VERSION 5.7 ;
  NOWIREEXTENSIONATPIN ON ;
  DIVIDERCHAR "/" ;
  BUSBITCHARS "[]" ;
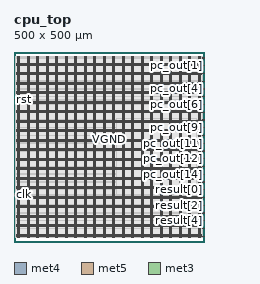
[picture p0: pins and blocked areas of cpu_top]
MACRO cpu_top
  CLASS BLOCK ;
  FOREIGN cpu_top ;
  ORIGIN 0.000 0.000 ;
  SIZE 500.000 BY 500.000 ;
  PIN VGND
    DIRECTION INOUT ;
    USE GROUND ;
    PORT
      LAYER met4 ;
        RECT 13.020 10.640 14.620 487.120 ;
    END
    PORT
      LAYER met4 ;
        RECT 38.020 10.640 39.620 487.120 ;
    END
    PORT
      LAYER met4 ;
        RECT 63.020 10.640 64.620 487.120 ;
    END
    PORT
      LAYER met4 ;
        RECT 88.020 10.640 89.620 487.120 ;
    END
    PORT
      LAYER met4 ;
        RECT 113.020 10.640 114.620 487.120 ;
    END
    PORT
      LAYER met4 ;
        RECT 138.020 10.640 139.620 487.120 ;
    END
    PORT
      LAYER met4 ;
        RECT 163.020 10.640 164.620 487.120 ;
    END
    PORT
      LAYER met4 ;
        RECT 188.020 10.640 189.620 487.120 ;
    END
    PORT
      LAYER met4 ;
        RECT 213.020 10.640 214.620 487.120 ;
    END
    PORT
      LAYER met4 ;
        RECT 238.020 10.640 239.620 487.120 ;
    END
    PORT
      LAYER met4 ;
        RECT 263.020 10.640 264.620 487.120 ;
    END
    PORT
      LAYER met4 ;
        RECT 288.020 10.640 289.620 487.120 ;
    END
    PORT
      LAYER met4 ;
        RECT 313.020 10.640 314.620 487.120 ;
    END
    PORT
      LAYER met4 ;
        RECT 338.020 10.640 339.620 487.120 ;
    END
    PORT
      LAYER met4 ;
        RECT 363.020 10.640 364.620 487.120 ;
    END
    PORT
      LAYER met4 ;
        RECT 388.020 10.640 389.620 487.120 ;
    END
    PORT
      LAYER met4 ;
        RECT 413.020 10.640 414.620 487.120 ;
    END
    PORT
      LAYER met4 ;
        RECT 438.020 10.640 439.620 487.120 ;
    END
    PORT
      LAYER met4 ;
        RECT 463.020 10.640 464.620 487.120 ;
    END
    PORT
      LAYER met4 ;
        RECT 488.020 10.640 489.620 487.120 ;
    END
    PORT
      LAYER met5 ;
        RECT 5.280 18.380 494.280 19.980 ;
    END
    PORT
      LAYER met5 ;
        RECT 5.280 43.380 494.280 44.980 ;
    END
    PORT
      LAYER met5 ;
        RECT 5.280 68.380 494.280 69.980 ;
    END
    PORT
      LAYER met5 ;
        RECT 5.280 93.380 494.280 94.980 ;
    END
    PORT
      LAYER met5 ;
        RECT 5.280 118.380 494.280 119.980 ;
    END
    PORT
      LAYER met5 ;
        RECT 5.280 143.380 494.280 144.980 ;
    END
    PORT
      LAYER met5 ;
        RECT 5.280 168.380 494.280 169.980 ;
    END
    PORT
      LAYER met5 ;
        RECT 5.280 193.380 494.280 194.980 ;
    END
    PORT
      LAYER met5 ;
        RECT 5.280 218.380 494.280 219.980 ;
    END
    PORT
      LAYER met5 ;
        RECT 5.280 243.380 494.280 244.980 ;
    END
    PORT
      LAYER met5 ;
        RECT 5.280 268.380 494.280 269.980 ;
    END
    PORT
      LAYER met5 ;
        RECT 5.280 293.380 494.280 294.980 ;
    END
    PORT
      LAYER met5 ;
        RECT 5.280 318.380 494.280 319.980 ;
    END
    PORT
      LAYER met5 ;
        RECT 5.280 343.380 494.280 344.980 ;
    END
    PORT
      LAYER met5 ;
        RECT 5.280 368.380 494.280 369.980 ;
    END
    PORT
      LAYER met5 ;
        RECT 5.280 393.380 494.280 394.980 ;
    END
    PORT
      LAYER met5 ;
        RECT 5.280 418.380 494.280 419.980 ;
    END
    PORT
      LAYER met5 ;
        RECT 5.280 443.380 494.280 444.980 ;
    END
    PORT
      LAYER met5 ;
        RECT 5.280 468.380 494.280 469.980 ;
    END
  END VGND
  PIN VPWR
    DIRECTION INOUT ;
    USE POWER ;
    PORT
      LAYER met4 ;
        RECT 9.720 10.640 11.320 487.120 ;
    END
    PORT
      LAYER met4 ;
        RECT 34.720 10.640 36.320 487.120 ;
    END
    PORT
      LAYER met4 ;
        RECT 59.720 10.640 61.320 487.120 ;
    END
    PORT
      LAYER met4 ;
        RECT 84.720 10.640 86.320 487.120 ;
    END
    PORT
      LAYER met4 ;
        RECT 109.720 10.640 111.320 487.120 ;
    END
    PORT
      LAYER met4 ;
        RECT 134.720 10.640 136.320 487.120 ;
    END
    PORT
      LAYER met4 ;
        RECT 159.720 10.640 161.320 487.120 ;
    END
    PORT
      LAYER met4 ;
        RECT 184.720 10.640 186.320 487.120 ;
    END
    PORT
      LAYER met4 ;
        RECT 209.720 10.640 211.320 487.120 ;
    END
    PORT
      LAYER met4 ;
        RECT 234.720 10.640 236.320 487.120 ;
    END
    PORT
      LAYER met4 ;
        RECT 259.720 10.640 261.320 487.120 ;
    END
    PORT
      LAYER met4 ;
        RECT 284.720 10.640 286.320 487.120 ;
    END
    PORT
      LAYER met4 ;
        RECT 309.720 10.640 311.320 487.120 ;
    END
    PORT
      LAYER met4 ;
        RECT 334.720 10.640 336.320 487.120 ;
    END
    PORT
      LAYER met4 ;
        RECT 359.720 10.640 361.320 487.120 ;
    END
    PORT
      LAYER met4 ;
        RECT 384.720 10.640 386.320 487.120 ;
    END
    PORT
      LAYER met4 ;
        RECT 409.720 10.640 411.320 487.120 ;
    END
    PORT
      LAYER met4 ;
        RECT 434.720 10.640 436.320 487.120 ;
    END
    PORT
      LAYER met4 ;
        RECT 459.720 10.640 461.320 487.120 ;
    END
    PORT
      LAYER met4 ;
        RECT 484.720 10.640 486.320 487.120 ;
    END
    PORT
      LAYER met5 ;
        RECT 5.280 15.080 494.280 16.680 ;
    END
    PORT
      LAYER met5 ;
        RECT 5.280 40.080 494.280 41.680 ;
    END
    PORT
      LAYER met5 ;
        RECT 5.280 65.080 494.280 66.680 ;
    END
    PORT
      LAYER met5 ;
        RECT 5.280 90.080 494.280 91.680 ;
    END
    PORT
      LAYER met5 ;
        RECT 5.280 115.080 494.280 116.680 ;
    END
    PORT
      LAYER met5 ;
        RECT 5.280 140.080 494.280 141.680 ;
    END
    PORT
      LAYER met5 ;
        RECT 5.280 165.080 494.280 166.680 ;
    END
    PORT
      LAYER met5 ;
        RECT 5.280 190.080 494.280 191.680 ;
    END
    PORT
      LAYER met5 ;
        RECT 5.280 215.080 494.280 216.680 ;
    END
    PORT
      LAYER met5 ;
        RECT 5.280 240.080 494.280 241.680 ;
    END
    PORT
      LAYER met5 ;
        RECT 5.280 265.080 494.280 266.680 ;
    END
    PORT
      LAYER met5 ;
        RECT 5.280 290.080 494.280 291.680 ;
    END
    PORT
      LAYER met5 ;
        RECT 5.280 315.080 494.280 316.680 ;
    END
    PORT
      LAYER met5 ;
        RECT 5.280 340.080 494.280 341.680 ;
    END
    PORT
      LAYER met5 ;
        RECT 5.280 365.080 494.280 366.680 ;
    END
    PORT
      LAYER met5 ;
        RECT 5.280 390.080 494.280 391.680 ;
    END
    PORT
      LAYER met5 ;
        RECT 5.280 415.080 494.280 416.680 ;
    END
    PORT
      LAYER met5 ;
        RECT 5.280 440.080 494.280 441.680 ;
    END
    PORT
      LAYER met5 ;
        RECT 5.280 465.080 494.280 466.680 ;
    END
  END VPWR
  PIN clk
    DIRECTION INPUT ;
    USE SIGNAL ;
    ANTENNAGATEAREA 0.852000 ;
    PORT
      LAYER met3 ;
        RECT 0.000 123.800 4.000 124.400 ;
    END
  END clk
  PIN pc_out[0]
    DIRECTION OUTPUT TRISTATE ;
    USE SIGNAL ;
    ANTENNAGATEAREA 1.984500 ;
    ANTENNADIFFAREA 0.445500 ;
    PORT
      LAYER met3 ;
        RECT 496.000 484.200 500.000 484.800 ;
    END
  END pc_out[0]
  PIN pc_out[10]
    DIRECTION OUTPUT TRISTATE ;
    USE SIGNAL ;
    ANTENNAGATEAREA 1.363500 ;
    ANTENNADIFFAREA 0.445500 ;
    PORT
      LAYER met3 ;
        RECT 496.000 280.200 500.000 280.800 ;
    END
  END pc_out[10]
  PIN pc_out[11]
    DIRECTION OUTPUT TRISTATE ;
    USE SIGNAL ;
    ANTENNAGATEAREA 0.621000 ;
    ANTENNADIFFAREA 0.445500 ;
    PORT
      LAYER met3 ;
        RECT 496.000 259.800 500.000 260.400 ;
    END
  END pc_out[11]
  PIN pc_out[12]
    DIRECTION OUTPUT TRISTATE ;
    USE SIGNAL ;
    ANTENNAGATEAREA 1.363500 ;
    ANTENNADIFFAREA 0.445500 ;
    PORT
      LAYER met3 ;
        RECT 496.000 239.400 500.000 240.000 ;
    END
  END pc_out[12]
  PIN pc_out[13]
    DIRECTION OUTPUT TRISTATE ;
    USE SIGNAL ;
    ANTENNAGATEAREA 0.621000 ;
    ANTENNADIFFAREA 0.445500 ;
    PORT
      LAYER met3 ;
        RECT 496.000 219.000 500.000 219.600 ;
    END
  END pc_out[13]
  PIN pc_out[14]
    DIRECTION OUTPUT TRISTATE ;
    USE SIGNAL ;
    ANTENNAGATEAREA 1.237500 ;
    ANTENNADIFFAREA 0.445500 ;
    PORT
      LAYER met3 ;
        RECT 496.000 198.600 500.000 199.200 ;
    END
  END pc_out[14]
  PIN pc_out[15]
    DIRECTION OUTPUT TRISTATE ;
    USE SIGNAL ;
    ANTENNAGATEAREA 0.742500 ;
    ANTENNADIFFAREA 0.445500 ;
    PORT
      LAYER met3 ;
        RECT 496.000 178.200 500.000 178.800 ;
    END
  END pc_out[15]
  PIN pc_out[1]
    DIRECTION OUTPUT TRISTATE ;
    USE SIGNAL ;
    ANTENNAGATEAREA 1.489500 ;
    ANTENNADIFFAREA 0.445500 ;
    PORT
      LAYER met3 ;
        RECT 496.000 463.800 500.000 464.400 ;
    END
  END pc_out[1]
  PIN pc_out[2]
    DIRECTION OUTPUT TRISTATE ;
    USE SIGNAL ;
    ANTENNAGATEAREA 0.747000 ;
    ANTENNADIFFAREA 0.445500 ;
    PORT
      LAYER met3 ;
        RECT 496.000 443.400 500.000 444.000 ;
    END
  END pc_out[2]
  PIN pc_out[3]
    DIRECTION OUTPUT TRISTATE ;
    USE SIGNAL ;
    ANTENNAGATEAREA 0.373500 ;
    ANTENNADIFFAREA 0.445500 ;
    PORT
      LAYER met3 ;
        RECT 496.000 423.000 500.000 423.600 ;
    END
  END pc_out[3]
  PIN pc_out[4]
    DIRECTION OUTPUT TRISTATE ;
    USE SIGNAL ;
    ANTENNAGATEAREA 2.106000 ;
    ANTENNADIFFAREA 0.445500 ;
    PORT
      LAYER met3 ;
        RECT 496.000 402.600 500.000 403.200 ;
    END
  END pc_out[4]
  PIN pc_out[5]
    DIRECTION OUTPUT TRISTATE ;
    USE SIGNAL ;
    ANTENNAGATEAREA 1.363500 ;
    ANTENNADIFFAREA 0.445500 ;
    PORT
      LAYER met3 ;
        RECT 496.000 382.200 500.000 382.800 ;
    END
  END pc_out[5]
  PIN pc_out[6]
    DIRECTION OUTPUT TRISTATE ;
    USE SIGNAL ;
    ANTENNAGATEAREA 0.621000 ;
    ANTENNADIFFAREA 0.445500 ;
    PORT
      LAYER met3 ;
        RECT 496.000 361.800 500.000 362.400 ;
    END
  END pc_out[6]
  PIN pc_out[7]
    DIRECTION OUTPUT TRISTATE ;
    USE SIGNAL ;
    ANTENNAGATEAREA 1.489500 ;
    ANTENNADIFFAREA 0.445500 ;
    PORT
      LAYER met3 ;
        RECT 496.000 341.400 500.000 342.000 ;
    END
  END pc_out[7]
  PIN pc_out[8]
    DIRECTION OUTPUT TRISTATE ;
    USE SIGNAL ;
    ANTENNAGATEAREA 0.747000 ;
    ANTENNADIFFAREA 0.445500 ;
    PORT
      LAYER met3 ;
        RECT 496.000 321.000 500.000 321.600 ;
    END
  END pc_out[8]
  PIN pc_out[9]
    DIRECTION OUTPUT TRISTATE ;
    USE SIGNAL ;
    ANTENNAGATEAREA 0.373500 ;
    ANTENNADIFFAREA 0.445500 ;
    PORT
      LAYER met3 ;
        RECT 496.000 300.600 500.000 301.200 ;
    END
  END pc_out[9]
  PIN result[0]
    DIRECTION OUTPUT TRISTATE ;
    USE SIGNAL ;
    PORT
      LAYER met3 ;
        RECT 496.000 157.800 500.000 158.400 ;
    END
  END result[0]
  PIN result[1]
    DIRECTION OUTPUT TRISTATE ;
    USE SIGNAL ;
    PORT
      LAYER met3 ;
        RECT 496.000 137.400 500.000 138.000 ;
    END
  END result[1]
  PIN result[2]
    DIRECTION OUTPUT TRISTATE ;
    USE SIGNAL ;
    PORT
      LAYER met3 ;
        RECT 496.000 117.000 500.000 117.600 ;
    END
  END result[2]
  PIN result[3]
    DIRECTION OUTPUT TRISTATE ;
    USE SIGNAL ;
    PORT
      LAYER met3 ;
        RECT 496.000 96.600 500.000 97.200 ;
    END
  END result[3]
  PIN result[4]
    DIRECTION OUTPUT TRISTATE ;
    USE SIGNAL ;
    PORT
      LAYER met3 ;
        RECT 496.000 76.200 500.000 76.800 ;
    END
  END result[4]
  PIN result[5]
    DIRECTION OUTPUT TRISTATE ;
    USE SIGNAL ;
    PORT
      LAYER met3 ;
        RECT 496.000 55.800 500.000 56.400 ;
    END
  END result[5]
  PIN result[6]
    DIRECTION OUTPUT TRISTATE ;
    USE SIGNAL ;
    PORT
      LAYER met3 ;
        RECT 496.000 35.400 500.000 36.000 ;
    END
  END result[6]
  PIN result[7]
    DIRECTION OUTPUT TRISTATE ;
    USE SIGNAL ;
    PORT
      LAYER met3 ;
        RECT 496.000 15.000 500.000 15.600 ;
    END
  END result[7]
  PIN rst
    DIRECTION INPUT ;
    USE SIGNAL ;
    ANTENNAGATEAREA 2.302500 ;
    PORT
      LAYER met3 ;
        RECT 0.000 374.040 4.000 374.640 ;
    END
  END rst
  OBS
      LAYER li1 ;
        RECT 5.520 10.795 494.040 486.965 ;
      LAYER met1 ;
        RECT 5.520 10.640 494.040 487.120 ;
      LAYER met2 ;
        RECT 8.840 10.695 489.590 487.065 ;
      LAYER met3 ;
        RECT 4.000 485.200 496.000 487.045 ;
        RECT 4.000 483.800 495.600 485.200 ;
        RECT 4.000 464.800 496.000 483.800 ;
        RECT 4.000 463.400 495.600 464.800 ;
        RECT 4.000 444.400 496.000 463.400 ;
        RECT 4.000 443.000 495.600 444.400 ;
        RECT 4.000 424.000 496.000 443.000 ;
        RECT 4.000 422.600 495.600 424.000 ;
        RECT 4.000 403.600 496.000 422.600 ;
        RECT 4.000 402.200 495.600 403.600 ;
        RECT 4.000 383.200 496.000 402.200 ;
        RECT 4.000 381.800 495.600 383.200 ;
        RECT 4.000 375.040 496.000 381.800 ;
        RECT 4.400 373.640 496.000 375.040 ;
        RECT 4.000 362.800 496.000 373.640 ;
        RECT 4.000 361.400 495.600 362.800 ;
        RECT 4.000 342.400 496.000 361.400 ;
        RECT 4.000 341.000 495.600 342.400 ;
        RECT 4.000 322.000 496.000 341.000 ;
        RECT 4.000 320.600 495.600 322.000 ;
        RECT 4.000 301.600 496.000 320.600 ;
        RECT 4.000 300.200 495.600 301.600 ;
        RECT 4.000 281.200 496.000 300.200 ;
        RECT 4.000 279.800 495.600 281.200 ;
        RECT 4.000 260.800 496.000 279.800 ;
        RECT 4.000 259.400 495.600 260.800 ;
        RECT 4.000 240.400 496.000 259.400 ;
        RECT 4.000 239.000 495.600 240.400 ;
        RECT 4.000 220.000 496.000 239.000 ;
        RECT 4.000 218.600 495.600 220.000 ;
        RECT 4.000 199.600 496.000 218.600 ;
        RECT 4.000 198.200 495.600 199.600 ;
        RECT 4.000 179.200 496.000 198.200 ;
        RECT 4.000 177.800 495.600 179.200 ;
        RECT 4.000 158.800 496.000 177.800 ;
        RECT 4.000 157.400 495.600 158.800 ;
        RECT 4.000 138.400 496.000 157.400 ;
        RECT 4.000 137.000 495.600 138.400 ;
        RECT 4.000 124.800 496.000 137.000 ;
        RECT 4.400 123.400 496.000 124.800 ;
        RECT 4.000 118.000 496.000 123.400 ;
        RECT 4.000 116.600 495.600 118.000 ;
        RECT 4.000 97.600 496.000 116.600 ;
        RECT 4.000 96.200 495.600 97.600 ;
        RECT 4.000 77.200 496.000 96.200 ;
        RECT 4.000 75.800 495.600 77.200 ;
        RECT 4.000 56.800 496.000 75.800 ;
        RECT 4.000 55.400 495.600 56.800 ;
        RECT 4.000 36.400 496.000 55.400 ;
        RECT 4.000 35.000 495.600 36.400 ;
        RECT 4.000 16.000 496.000 35.000 ;
        RECT 4.000 14.600 495.600 16.000 ;
        RECT 4.000 10.715 496.000 14.600 ;
      LAYER met4 ;
        RECT 270.775 123.935 284.320 324.865 ;
        RECT 286.720 123.935 287.620 324.865 ;
        RECT 290.020 123.935 309.320 324.865 ;
        RECT 311.720 123.935 312.620 324.865 ;
        RECT 315.020 123.935 334.320 324.865 ;
        RECT 336.720 123.935 337.620 324.865 ;
        RECT 340.020 123.935 359.320 324.865 ;
        RECT 361.720 123.935 362.620 324.865 ;
        RECT 365.020 123.935 384.320 324.865 ;
        RECT 386.720 123.935 387.620 324.865 ;
        RECT 390.020 123.935 409.320 324.865 ;
        RECT 411.720 123.935 412.620 324.865 ;
        RECT 415.020 123.935 434.320 324.865 ;
        RECT 436.720 123.935 437.620 324.865 ;
        RECT 440.020 123.935 459.320 324.865 ;
        RECT 461.720 123.935 462.620 324.865 ;
        RECT 465.020 123.935 479.945 324.865 ;
  END
END cpu_top
END LIBRARY

